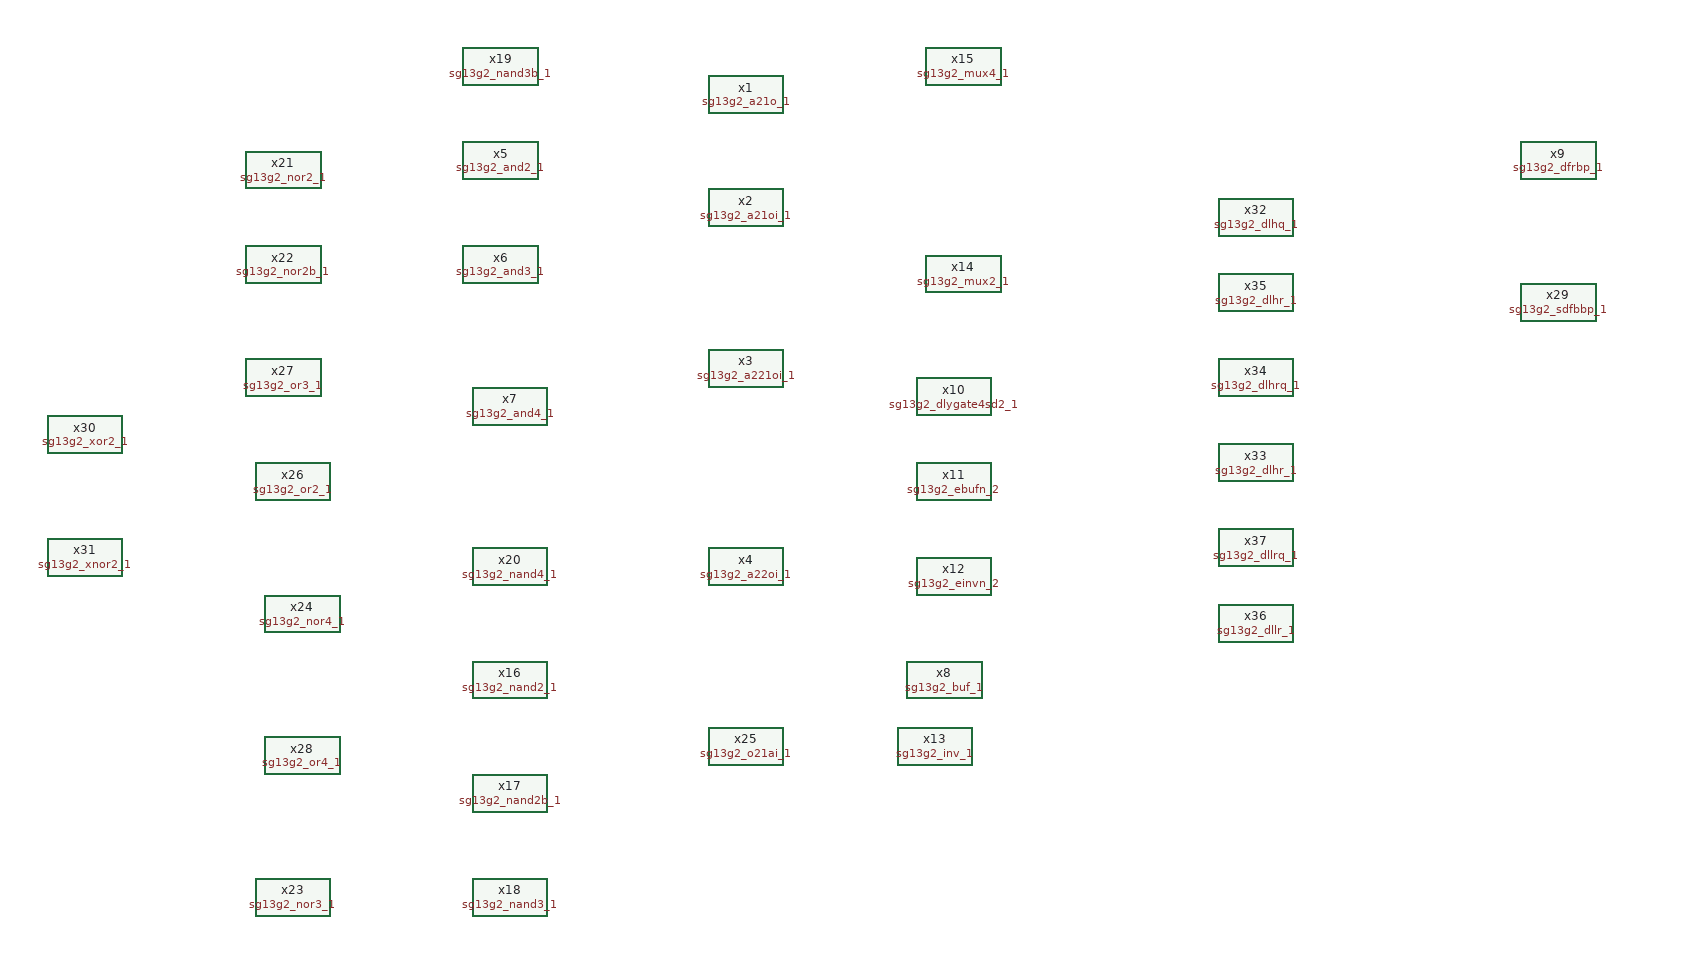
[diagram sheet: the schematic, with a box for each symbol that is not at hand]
v {xschem version=3.4.4 file_version=1.2
}
G {}
K {}
V {}
S {}
E {}
C {devices/title.sym} -90 0 0 0 {name=l1 author="IHP PDK Authors"}
C {sg13g2_stdcells/sg13g2_a21o_1.sym} 330 -970 0 0 {name=x1 VGND=VGND VNB=VNB VPB=VPB VPWR=VPWR prefix=sg13g2_ }
C {sg13g2_stdcells/sg13g2_a21oi_1.sym} 330 -850 0 0 {name=x2 VGND=VGND VNB=VNB VPB=VPB VPWR=VPWR prefix=sg13g2_ }
C {sg13g2_stdcells/sg13g2_a221oi_1.sym} 330 -680 0 0 {name=x3 VGND=VGND VNB=VNB VPB=VPB VPWR=VPWR prefix=sg13g2_ }
C {sg13g2_stdcells/sg13g2_a22oi_1.sym} 330 -470 0 0 {name=x4 VGND=VGND VNB=VNB VPB=VPB VPWR=VPWR prefix=sg13g2_ }
C {sg13g2_stdcells/sg13g2_and2_1.sym} 70 -900 0 0 {name=x5 VGND=VGND VNB=VNB VPB=VPB VPWR=VPWR prefix=sg13g2_ }
C {sg13g2_stdcells/sg13g2_and3_1.sym} 70 -790 0 0 {name=x6 VGND=VGND VNB=VNB VPB=VPB VPWR=VPWR prefix=sg13g2_ }
C {sg13g2_stdcells/sg13g2_and4_1.sym} 80 -640 0 0 {name=x7 VGND=VGND VNB=VNB VPB=VPB VPWR=VPWR prefix=sg13g2_ }
C {sg13g2_stdcells/sg13g2_buf_1.sym} 540 -350 0 0 {name=x8 VGND=VGND VNB=VNB VPB=VPB VPWR=VPWR prefix=sg13g2_ }
C {sg13g2_stdcells/sg13g2_dfrbp_1.sym} 1190 -900 0 0 {name=x9 VGND=VGND VNB=VNB VPB=VPB VPWR=VPWR prefix=sg13g2_ }
C {sg13g2_stdcells/sg13g2_dlygate4sd2_1.sym} 550 -650 0 0 {name=x10 VGND=VGND VNB=VNB VPB=VPB VPWR=VPWR prefix=sg13g2_ }
C {sg13g2_stdcells/sg13g2_ebufn_2.sym} 550 -560 0 0 {name=x11 VGND=VGND VNB=VNB VPB=VPB VPWR=VPWR prefix=sg13g2_ }
C {sg13g2_stdcells/sg13g2_einvn_2.sym} 550 -460 0 0 {name=x12 VGND=VGND VNB=VNB VPB=VPB VPWR=VPWR prefix=sg13g2_ }
C {sg13g2_stdcells/sg13g2_inv_1.sym} 530 -280 0 0 {name=x13 VGND=VGND VNB=VNB VPB=VPB VPWR=VPWR prefix=sg13g2_ }
C {sg13g2_stdcells/sg13g2_mux2_1.sym} 560 -780 0 0 {name=x14 VGND=VGND VNB=VNB VPB=VPB VPWR=VPWR prefix=sg13g2_ }
C {sg13g2_stdcells/sg13g2_mux4_1.sym} 560 -1000 0 0 {name=x15 VGND=VGND VNB=VNB VPB=VPB VPWR=VPWR prefix=sg13g2_ }
C {sg13g2_stdcells/sg13g2_nand2_1.sym} 80 -350 0 0 {name=x16 VGND=VGND VNB=VNB VPB=VPB VPWR=VPWR prefix=sg13g2_ }
C {sg13g2_stdcells/sg13g2_nand2b_1.sym} 80 -230 0 0 {name=x17 VGND=VGND VNB=VNB VPB=VPB VPWR=VPWR prefix=sg13g2_ }
C {sg13g2_stdcells/sg13g2_nand3_1.sym} 80 -120 0 0 {name=x18 VGND=VGND VNB=VNB VPB=VPB VPWR=VPWR prefix=sg13g2_ }
C {sg13g2_stdcells/sg13g2_nand3b_1.sym} 70 -1000 0 0 {name=x19 VGND=VGND VNB=VNB VPB=VPB VPWR=VPWR prefix=sg13g2_ }
C {sg13g2_stdcells/sg13g2_nand4_1.sym} 80 -470 0 0 {name=x20 VGND=VGND VNB=VNB VPB=VPB VPWR=VPWR prefix=sg13g2_ }
C {sg13g2_stdcells/sg13g2_nor2_1.sym} -160 -890 0 0 {name=x21 VGND=VGND VNB=VNB VPB=VPB VPWR=VPWR prefix=sg13g2_ }
C {sg13g2_stdcells/sg13g2_nor2b_1.sym} -160 -790 0 0 {name=x22 VGND=VGND VNB=VNB VPB=VPB VPWR=VPWR prefix=sg13g2_ }
C {sg13g2_stdcells/sg13g2_nor3_1.sym} -150 -120 0 0 {name=x23 VGND=VGND VNB=VNB VPB=VPB VPWR=VPWR prefix=sg13g2_ }
C {sg13g2_stdcells/sg13g2_nor4_1.sym} -140 -420 0 0 {name=x24 VGND=VGND VNB=VNB VPB=VPB VPWR=VPWR prefix=sg13g2_ }
C {sg13g2_stdcells/sg13g2_o21ai_1.sym} 330 -280 0 0 {name=x25 VGND=VGND VNB=VNB VPB=VPB VPWR=VPWR prefix=sg13g2_ }
C {sg13g2_stdcells/sg13g2_or2_1.sym} -150 -560 0 0 {name=x26 VGND=VGND VNB=VNB VPB=VPB VPWR=VPWR prefix=sg13g2_ }
C {sg13g2_stdcells/sg13g2_or3_1.sym} -160 -670 0 0 {name=x27 VGND=VGND VNB=VNB VPB=VPB VPWR=VPWR prefix=sg13g2_ }
C {sg13g2_stdcells/sg13g2_or4_1.sym} -140 -270 0 0 {name=x28 VGND=VGND VNB=VNB VPB=VPB VPWR=VPWR prefix=sg13g2_ }
C {sg13g2_stdcells/sg13g2_sdfbbp_1.sym} 1190 -750 0 0 {name=x29 VGND=VGND VNB=VNB VPB=VPB VPWR=VPWR prefix=sg13g2_ }
C {sg13g2_stdcells/sg13g2_xor2_1.sym} -370 -610 0 0 {name=x30 VGND=VGND VNB=VNB VPB=VPB VPWR=VPWR prefix=sg13g2_ }
C {sg13g2_stdcells/sg13g2_xnor2_1.sym} -370 -480 0 0 {name=x31 VGND=VGND VNB=VNB VPB=VPB VPWR=VPWR prefix=sg13g2_ }
C {sg13g2_stdcells/sg13g2_dlhq_1.sym} 870 -840 0 0 {name=x32 VGND=VGND VNB=VNB VPB=VPB VPWR=VPWR prefix=sg13g2_ }
C {sg13g2_stdcells/sg13g2_dlhr_1.sym} 870 -580 0 0 {name=x33 VGND=VGND VNB=VNB VPB=VPB VPWR=VPWR prefix=sg13g2_ }
C {sg13g2_stdcells/sg13g2_dlhrq_1.sym} 870 -670 0 0 {name=x34 VGND=VGND VNB=VNB VPB=VPB VPWR=VPWR prefix=sg13g2_ }
C {sg13g2_stdcells/sg13g2_dlhr_1.sym} 870 -760 0 0 {name=x35 VGND=VGND VNB=VNB VPB=VPB VPWR=VPWR prefix=sg13g2_ }
C {sg13g2_stdcells/sg13g2_dllr_1.sym} 870 -410 0 0 {name=x36 VGND=VGND VNB=VNB VPB=VPB VPWR=VPWR prefix=sg13g2_ }
C {sg13g2_stdcells/sg13g2_dllrq_1.sym} 870 -490 0 0 {name=x37 VGND=VGND VNB=VNB VPB=VPB VPWR=VPWR prefix=sg13g2_ }
